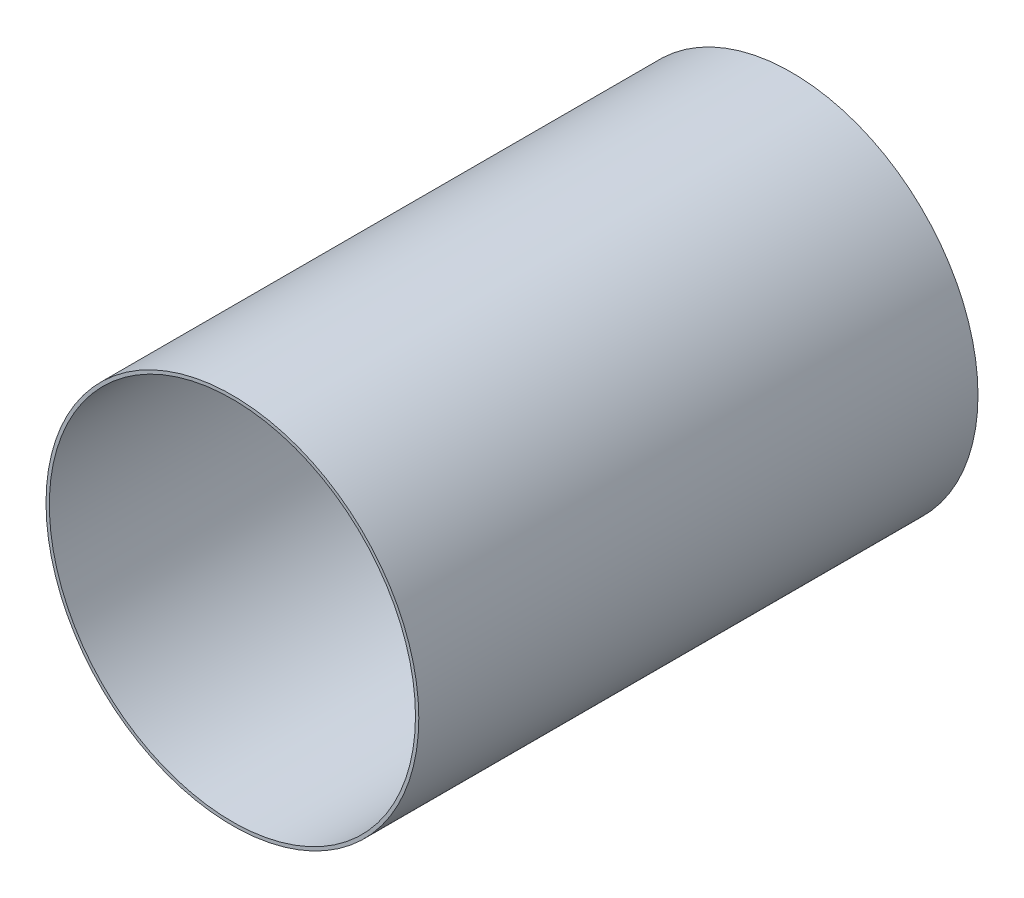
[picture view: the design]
ISO-10303-21;
HEADER;
FILE_DESCRIPTION(('STEP AP214'),'2;1');
FILE_NAME('part.step','',(''),(''),'','','');
FILE_SCHEMA(('AUTOMOTIVE_DESIGN { 1 0 10303 214 1 1 1 1 }'));
ENDSEC;
DATA;
#1=APPLICATION_CONTEXT('core data for automotive mechanical design processes');
#2=APPLICATION_PROTOCOL_DEFINITION('international standard','automotive_design',2000,#1);
#3=PRODUCT_CONTEXT('',#1,'mechanical');
#4=PRODUCT('Part','Part','',(#3));
#5=PRODUCT_RELATED_PRODUCT_CATEGORY('part','',(#4));
#6=PRODUCT_DEFINITION_FORMATION('','',#4);
#7=PRODUCT_DEFINITION_CONTEXT('part definition',#1,'design');
#8=PRODUCT_DEFINITION('design','',#6,#7);
#9=PRODUCT_DEFINITION_SHAPE('','',#8);
#10=(LENGTH_UNIT() NAMED_UNIT(*) SI_UNIT(.MILLI.,.METRE.));
#11=(NAMED_UNIT(*) PLANE_ANGLE_UNIT() SI_UNIT($,.RADIAN.));
#12=(NAMED_UNIT(*) SI_UNIT($,.STERADIAN.) SOLID_ANGLE_UNIT());
#13=UNCERTAINTY_MEASURE_WITH_UNIT(LENGTH_MEASURE(1.E-05),#10,'distance_accuracy_value','');
#14=(GEOMETRIC_REPRESENTATION_CONTEXT(3) GLOBAL_UNCERTAINTY_ASSIGNED_CONTEXT((#13)) GLOBAL_UNIT_ASSIGNED_CONTEXT((#10,
#11,#12)) REPRESENTATION_CONTEXT('',''));
#15=CARTESIAN_POINT('',(0.,0.,0.));
#16=DIRECTION('',(0.,0.,1.));
#17=DIRECTION('',(1.,0.,0.));
#18=AXIS2_PLACEMENT_3D('',#15,#16,#17);
#19=CARTESIAN_POINT('',(0.,0.,2133.6));
#20=DIRECTION('',(0.,0.,1.));
#21=DIRECTION('',(1.,0.,0.));
#22=AXIS2_PLACEMENT_3D('',#19,#20,#21);
#23=PLANE('',#22);
#24=CARTESIAN_POINT('',(0.,0.,2133.6));
#25=DIRECTION('',(0.,0.,1.));
#26=DIRECTION('',(1.,0.,0.));
#27=AXIS2_PLACEMENT_3D('',#24,#25,#26);
#28=CIRCLE('',#27,711.2);
#29=CARTESIAN_POINT('',(711.2,0.,2133.6));
#30=VERTEX_POINT('',#29);
#31=EDGE_CURVE('E10',#30,#30,#28,.T.);
#32=ORIENTED_EDGE('',*,*,#31,.T.);
#33=EDGE_LOOP('',(#32));
#34=FACE_BOUND('',#33,.T.);
#35=CARTESIAN_POINT('',(0.,0.,2133.6));
#36=DIRECTION('',(0.,0.,1.));
#37=DIRECTION('',(1.,0.,0.));
#38=AXIS2_PLACEMENT_3D('',#35,#36,#37);
#39=CIRCLE('',#38,698.5);
#40=CARTESIAN_POINT('',(698.5,0.,2133.6));
#41=VERTEX_POINT('',#40);
#42=EDGE_CURVE('E51',#41,#41,#39,.T.);
#43=ORIENTED_EDGE('',*,*,#42,.F.);
#44=EDGE_LOOP('',(#43));
#45=FACE_BOUND('',#44,.T.);
#46=ADVANCED_FACE('F32',(#34,#45),#23,.T.);
#47=CARTESIAN_POINT('',(0.,0.,0.));
#48=DIRECTION('',(0.,0.,1.));
#49=DIRECTION('',(1.,0.,0.));
#50=AXIS2_PLACEMENT_3D('',#47,#48,#49);
#51=PLANE('',#50);
#52=CARTESIAN_POINT('',(0.,0.,0.));
#53=DIRECTION('',(0.,0.,1.));
#54=DIRECTION('',(1.,0.,0.));
#55=AXIS2_PLACEMENT_3D('',#52,#53,#54);
#56=CIRCLE('',#55,711.2);
#57=CARTESIAN_POINT('',(711.2,0.,0.));
#58=VERTEX_POINT('',#57);
#59=EDGE_CURVE('E46',#58,#58,#56,.T.);
#60=ORIENTED_EDGE('',*,*,#59,.F.);
#61=EDGE_LOOP('',(#60));
#62=FACE_BOUND('',#61,.T.);
#63=CARTESIAN_POINT('',(0.,0.,0.));
#64=DIRECTION('',(0.,0.,1.));
#65=DIRECTION('',(1.,0.,0.));
#66=AXIS2_PLACEMENT_3D('',#63,#64,#65);
#67=CIRCLE('',#66,698.5);
#68=CARTESIAN_POINT('',(698.5,0.,0.));
#69=VERTEX_POINT('',#68);
#70=EDGE_CURVE('E53',#69,#69,#67,.T.);
#71=ORIENTED_EDGE('',*,*,#70,.T.);
#72=EDGE_LOOP('',(#71));
#73=FACE_BOUND('',#72,.T.);
#74=ADVANCED_FACE('F74',(#62,#73),#51,.F.);
#75=CARTESIAN_POINT('',(0.,0.,2133.6));
#76=DIRECTION('',(0.,0.,-1.));
#77=DIRECTION('',(-1.,0.,0.));
#78=AXIS2_PLACEMENT_3D('',#75,#76,#77);
#79=CYLINDRICAL_SURFACE('',#78,711.2);
#80=CARTESIAN_POINT('',(-711.2,0.,1071.5625));
#81=CARTESIAN_POINT('',(-711.199996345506,-4.13113994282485,1071.56249542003));
#82=CARTESIAN_POINT('',(-711.16398099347,-8.26258775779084,1071.47977653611));
#83=CARTESIAN_POINT('',(-711.020141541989,-16.5180823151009,1071.14909768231));
#84=CARTESIAN_POINT('',(-710.912306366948,-20.6421278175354,1070.90111222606));
#85=CARTESIAN_POINT('',(-710.625466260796,-28.8767675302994,1070.24039880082));
#86=CARTESIAN_POINT('',(-710.446423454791,-32.987353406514,1069.82758315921));
#87=CARTESIAN_POINT('',(-710.018370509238,-41.1849399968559,1068.83837206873));
#88=CARTESIAN_POINT('',(-709.769363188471,-45.2719416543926,1068.26198321));
#89=CARTESIAN_POINT('',(-709.202396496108,-53.424083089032,1066.94572322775));
#90=CARTESIAN_POINT('',(-708.884284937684,-57.4891539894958,1066.2054912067));
#91=CARTESIAN_POINT('',(-708.18152615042,-65.5809359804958,1064.56424978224));
#92=CARTESIAN_POINT('',(-707.796878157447,-69.6076466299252,1063.66323853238));
#93=CARTESIAN_POINT('',(-706.963617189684,-77.6149766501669,1061.70292681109));
#94=CARTESIAN_POINT('',(-706.515014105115,-81.5956030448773,1060.643650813));
#95=CARTESIAN_POINT('',(-705.556680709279,-89.5046269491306,1058.36935486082));
#96=CARTESIAN_POINT('',(-705.046950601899,-93.4330246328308,1057.15433542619));
#97=CARTESIAN_POINT('',(-703.971483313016,-101.217464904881,1054.57600474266));
#98=CARTESIAN_POINT('',(-703.405949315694,-105.073713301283,1053.21322980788));
#99=CARTESIAN_POINT('',(-702.220888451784,-112.721954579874,1050.33902208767));
#100=CARTESIAN_POINT('',(-701.601361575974,-116.513947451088,1048.82758927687));
#101=CARTESIAN_POINT('',(-700.312078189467,-124.02808090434,1045.65930647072));
#102=CARTESIAN_POINT('',(-699.642320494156,-127.750219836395,1044.0024530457));
#103=CARTESIAN_POINT('',(-698.256611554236,-135.119207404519,1040.54676856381));
#104=CARTESIAN_POINT('',(-697.540660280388,-138.766055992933,1038.74793741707));
#105=CARTESIAN_POINT('',(-696.067066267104,-145.978152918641,1035.01246595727));
#106=CARTESIAN_POINT('',(-695.309438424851,-149.543429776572,1033.07587481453));
#107=CARTESIAN_POINT('',(-693.7566859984,-156.588995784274,1029.06788260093));
#108=CARTESIAN_POINT('',(-692.961561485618,-160.069285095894,1026.99648178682));
#109=CARTESIAN_POINT('',(-691.338392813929,-166.940495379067,1022.72242513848));
#110=CARTESIAN_POINT('',(-690.510348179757,-170.331415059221,1020.51976740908));
#111=CARTESIAN_POINT('',(-688.826079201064,-177.019675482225,1015.98680379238));
#112=CARTESIAN_POINT('',(-687.969854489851,-180.317015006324,1013.65649624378));
#113=CARTESIAN_POINT('',(-686.19141053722,-186.973884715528,1008.75417774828));
#114=CARTESIAN_POINT('',(-685.268016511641,-190.328499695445,1006.17591614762));
#115=CARTESIAN_POINT('',(-683.401318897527,-196.925951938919,1000.88697345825));
#116=CARTESIAN_POINT('',(-682.458015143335,-200.168788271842,998.17629126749));
#117=CARTESIAN_POINT('',(-680.557390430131,-206.538433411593,992.626666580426));
#118=CARTESIAN_POINT('',(-679.600069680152,-209.665243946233,989.787725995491));
#119=CARTESIAN_POINT('',(-677.677307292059,-215.799069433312,983.985420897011));
#120=CARTESIAN_POINT('',(-676.711865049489,-218.8060753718,981.022047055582));
#121=CARTESIAN_POINT('',(-674.778525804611,-224.697569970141,974.97364991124));
#122=CARTESIAN_POINT('',(-673.810627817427,-227.58199671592,971.888566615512));
#123=CARTESIAN_POINT('',(-671.879027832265,-233.222854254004,965.602249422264));
#124=CARTESIAN_POINT('',(-670.915325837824,-235.979284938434,962.401015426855));
#125=CARTESIAN_POINT('',(-668.998290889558,-241.360488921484,955.886323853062));
#126=CARTESIAN_POINT('',(-668.044958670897,-243.985252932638,952.572858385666));
#127=CARTESIAN_POINT('',(-666.155107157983,-249.098861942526,945.838441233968));
#128=CARTESIAN_POINT('',(-665.218586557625,-251.587717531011,942.417497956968));
#129=CARTESIAN_POINT('',(-663.317723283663,-256.558967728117,935.281195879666));
#130=CARTESIAN_POINT('',(-662.354683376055,-259.033478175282,931.559992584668));
#131=CARTESIAN_POINT('',(-660.461716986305,-263.822650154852,924.007850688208));
#132=CARTESIAN_POINT('',(-659.531790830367,-266.137310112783,920.176911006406));
#133=CARTESIAN_POINT('',(-657.712428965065,-270.602315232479,912.410743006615));
#134=CARTESIAN_POINT('',(-656.8229954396,-272.75265153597,908.475509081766));
#135=CARTESIAN_POINT('',(-655.092019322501,-276.884277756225,900.506966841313));
#136=CARTESIAN_POINT('',(-654.250476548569,-278.865568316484,896.473658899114));
#137=CARTESIAN_POINT('',(-652.622823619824,-282.653743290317,888.317116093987));
#138=CARTESIAN_POINT('',(-651.836690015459,-284.4607016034,884.19392025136));
#139=CARTESIAN_POINT('',(-650.32642798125,-287.896681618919,875.862834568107));
#140=CARTESIAN_POINT('',(-649.602299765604,-289.525702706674,871.654944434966));
#141=CARTESIAN_POINT('',(-648.222752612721,-292.601339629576,863.162209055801));
#142=CARTESIAN_POINT('',(-647.567329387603,-294.047966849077,858.877368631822));
#143=CARTESIAN_POINT('',(-646.331389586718,-296.75476252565,850.238542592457));
#144=CARTESIAN_POINT('',(-645.750872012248,-298.014933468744,845.88455789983));
#145=CARTESIAN_POINT('',(-644.698085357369,-300.285369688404,837.34033540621));
#146=CARTESIAN_POINT('',(-644.221798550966,-301.305119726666,833.153111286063));
#147=CARTESIAN_POINT('',(-643.346153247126,-303.170297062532,824.732048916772));
#148=CARTESIAN_POINT('',(-642.94679393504,-304.01572620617,820.498211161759));
#149=CARTESIAN_POINT('',(-642.228752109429,-305.529658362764,811.992294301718));
#150=CARTESIAN_POINT('',(-641.910068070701,-306.19816472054,807.720215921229));
#151=CARTESIAN_POINT('',(-641.356419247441,-307.356138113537,799.146442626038));
#152=CARTESIAN_POINT('',(-641.12145454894,-307.845604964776,794.844747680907));
#153=CARTESIAN_POINT('',(-640.737638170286,-308.643670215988,786.223099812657));
#154=CARTESIAN_POINT('',(-640.588740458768,-308.952365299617,781.903157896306));
#155=CARTESIAN_POINT('',(-640.378330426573,-309.388255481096,773.251975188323));
#156=CARTESIAN_POINT('',(-640.316818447,-309.51544987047,768.920734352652));
#157=CARTESIAN_POINT('',(-640.281791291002,-309.587902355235,760.256609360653));
#158=CARTESIAN_POINT('',(-640.30827150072,-309.533169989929,755.923725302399));
#159=CARTESIAN_POINT('',(-640.448957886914,-309.241974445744,747.265550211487));
#160=CARTESIAN_POINT('',(-640.563162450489,-309.005514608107,742.940259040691));
#161=CARTESIAN_POINT('',(-640.864723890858,-308.379562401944,734.674739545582));
#162=CARTESIAN_POINT('',(-641.045013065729,-308.004837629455,730.73312456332));
#163=CARTESIAN_POINT('',(-641.476552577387,-307.105066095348,722.871051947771));
#164=CARTESIAN_POINT('',(-641.727801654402,-306.580022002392,718.950593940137));
#165=CARTESIAN_POINT('',(-642.299212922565,-305.38107630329,711.137853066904));
#166=CARTESIAN_POINT('',(-642.619370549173,-304.707184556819,707.245568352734));
#167=CARTESIAN_POINT('',(-643.326067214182,-303.212292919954,699.49542547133));
#168=CARTESIAN_POINT('',(-643.712606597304,-302.391292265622,695.637567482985));
#169=CARTESIAN_POINT('',(-644.549121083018,-300.604131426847,687.961988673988));
#170=CARTESIAN_POINT('',(-644.999105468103,-299.637949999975,684.144273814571));
#171=CARTESIAN_POINT('',(-645.959050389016,-297.562853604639,676.555494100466));
#172=CARTESIAN_POINT('',(-646.469010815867,-296.453938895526,672.784429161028));
#173=CARTESIAN_POINT('',(-647.545157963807,-294.095882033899,665.294419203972));
#174=CARTESIAN_POINT('',(-648.111346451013,-292.846735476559,661.575475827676));
#175=CARTESIAN_POINT('',(-649.295874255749,-290.210949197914,654.195078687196));
#176=CARTESIAN_POINT('',(-649.914213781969,-288.824308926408,650.533625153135));
#177=CARTESIAN_POINT('',(-651.212893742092,-285.884322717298,643.193142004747));
#178=CARTESIAN_POINT('',(-651.894300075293,-284.327976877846,639.515502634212));
#179=CARTESIAN_POINT('',(-653.302294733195,-281.077726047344,632.230346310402));
#180=CARTESIAN_POINT('',(-654.028883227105,-279.383820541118,628.622829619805));
#181=CARTESIAN_POINT('',(-655.522250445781,-275.861700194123,621.482706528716));
#182=CARTESIAN_POINT('',(-656.289027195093,-274.03349195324,617.950096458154));
#183=CARTESIAN_POINT('',(-657.857806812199,-270.245718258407,610.96363317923));
#184=CARTESIAN_POINT('',(-658.659812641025,-268.286141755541,607.50978662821));
#185=CARTESIAN_POINT('',(-660.294055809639,-264.238461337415,600.684398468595));
#186=CARTESIAN_POINT('',(-661.126300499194,-262.15032608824,597.312877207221));
#187=CARTESIAN_POINT('',(-662.815719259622,-257.848989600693,590.656651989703));
#188=CARTESIAN_POINT('',(-663.672895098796,-255.635779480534,587.371954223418));
#189=CARTESIAN_POINT('',(-665.406937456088,-251.087575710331,580.893303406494));
#190=CARTESIAN_POINT('',(-666.283804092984,-248.752581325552,577.699350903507));
#191=CARTESIAN_POINT('',(-668.052051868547,-243.963953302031,571.405754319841));
#192=CARTESIAN_POINT('',(-668.943433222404,-241.510317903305,568.306111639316));
#193=CARTESIAN_POINT('',(-670.819043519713,-236.253564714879,561.92038299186));
#194=CARTESIAN_POINT('',(-671.804186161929,-233.439183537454,558.643828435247));
#195=CARTESIAN_POINT('',(-673.778904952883,-227.67675080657,552.212297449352));
#196=CARTESIAN_POINT('',(-674.768480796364,-224.728708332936,549.057312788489));
#197=CARTESIAN_POINT('',(-676.74568166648,-218.70249113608,542.872626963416));
#198=CARTESIAN_POINT('',(-677.733306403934,-215.624298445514,539.842943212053));
#199=CARTESIAN_POINT('',(-679.699867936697,-209.342685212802,533.913979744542));
#200=CARTESIAN_POINT('',(-680.678805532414,-206.13927635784,531.01468791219));
#201=CARTESIAN_POINT('',(-682.622009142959,-199.610213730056,525.349645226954));
#202=CARTESIAN_POINT('',(-683.586270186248,-196.284519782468,522.583938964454));
#203=CARTESIAN_POINT('',(-685.493500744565,-189.516388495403,517.19150073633));
#204=CARTESIAN_POINT('',(-686.436470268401,-186.073951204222,514.564768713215));
#205=CARTESIAN_POINT('',(-688.294968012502,-179.077021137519,509.454698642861));
#206=CARTESIAN_POINT('',(-689.210496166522,-175.52252809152,506.971360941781));
#207=CARTESIAN_POINT('',(-691.008110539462,-168.306437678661,502.152529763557));
#208=CARTESIAN_POINT('',(-691.890196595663,-164.644839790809,499.81703700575));
#209=CARTESIAN_POINT('',(-693.638735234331,-157.118038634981,495.236434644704));
#210=CARTESIAN_POINT('',(-694.50409708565,-153.250005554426,492.995555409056));
#211=CARTESIAN_POINT('',(-696.187268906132,-145.412487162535,488.679375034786));
#212=CARTESIAN_POINT('',(-697.005078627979,-141.443001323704,486.604074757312));
#213=CARTESIAN_POINT('',(-698.58733315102,-133.408922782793,482.623732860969));
#214=CARTESIAN_POINT('',(-699.351775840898,-129.344326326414,480.718697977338));
#215=CARTESIAN_POINT('',(-700.821713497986,-121.127148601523,477.083628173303));
#216=CARTESIAN_POINT('',(-701.527208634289,-116.974567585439,475.353592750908));
#217=CARTESIAN_POINT('',(-702.873730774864,-108.590858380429,472.073771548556));
#218=CARTESIAN_POINT('',(-703.514788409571,-104.359768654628,470.523900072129));
#219=CARTESIAN_POINT('',(-704.728019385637,-95.8250317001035,467.607674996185));
#220=CARTESIAN_POINT('',(-705.300192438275,-91.5213841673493,466.24132216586));
#221=CARTESIAN_POINT('',(-706.371256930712,-82.8502850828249,463.696150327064));
#222=CARTESIAN_POINT('',(-706.870153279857,-78.4828378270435,462.517318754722));
#223=CARTESIAN_POINT('',(-707.79084372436,-69.6928131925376,460.350630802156));
#224=CARTESIAN_POINT('',(-708.21263910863,-65.2702367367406,459.362771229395));
#225=CARTESIAN_POINT('',(-708.949960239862,-56.6806478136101,457.641477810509));
#226=CARTESIAN_POINT('',(-709.270750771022,-52.5166283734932,456.895338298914));
#227=CARTESIAN_POINT('',(-709.840247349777,-44.1567134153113,455.57377072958));
#228=CARTESIAN_POINT('',(-710.088954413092,-39.9608183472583,454.998340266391));
#229=CARTESIAN_POINT('',(-710.512544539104,-31.5454133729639,454.01985150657));
#230=CARTESIAN_POINT('',(-710.687430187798,-27.3259042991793,453.616787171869));
#231=CARTESIAN_POINT('',(-710.962162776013,-18.8714422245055,452.984175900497));
#232=CARTESIAN_POINT('',(-711.062009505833,-14.6364891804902,452.754629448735));
#233=CARTESIAN_POINT('',(-711.185941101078,-6.16079425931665,452.469774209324));
#234=CARTESIAN_POINT('',(-711.210046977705,-1.92005431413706,452.414417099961));
#235=CARTESIAN_POINT('',(-711.182385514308,6.55988076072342,452.477968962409));
#236=CARTESIAN_POINT('',(-711.130618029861,10.7990758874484,452.596878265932));
#237=CARTESIAN_POINT('',(-710.951578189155,19.2673039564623,453.008604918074));
#238=CARTESIAN_POINT('',(-710.824307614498,23.4963371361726,453.301418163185));
#239=CARTESIAN_POINT('',(-710.495159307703,31.9359003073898,454.060087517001));
#240=CARTESIAN_POINT('',(-710.293282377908,36.1464304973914,454.525941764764));
#241=CARTESIAN_POINT('',(-709.829537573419,44.3084649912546,455.598802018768));
#242=CARTESIAN_POINT('',(-709.571606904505,48.2614113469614,456.196572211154));
#243=CARTESIAN_POINT('',(-708.992036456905,56.1366237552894,457.543797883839));
#244=CARTESIAN_POINT('',(-708.670397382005,60.0588901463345,458.293251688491));
#245=CARTESIAN_POINT('',(-707.965400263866,67.8659973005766,459.941951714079));
#246=CARTESIAN_POINT('',(-707.582045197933,71.7508398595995,460.841190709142));
#247=CARTESIAN_POINT('',(-706.755929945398,79.4769752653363,462.787329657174));
#248=CARTESIAN_POINT('',(-706.31316955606,83.3182679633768,463.834230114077));
#249=CARTESIAN_POINT('',(-705.370867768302,90.9514619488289,466.073330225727));
#250=CARTESIAN_POINT('',(-704.871322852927,94.74336016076,467.265538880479));
#251=CARTESIAN_POINT('',(-703.818426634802,102.271739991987,469.792542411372));
#252=CARTESIAN_POINT('',(-703.265075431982,106.008221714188,471.127337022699));
#253=CARTESIAN_POINT('',(-702.107770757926,113.420407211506,473.936705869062));
#254=CARTESIAN_POINT('',(-701.503815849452,117.096109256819,475.411284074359));
#255=CARTESIAN_POINT('',(-700.248780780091,124.381462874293,478.497190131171));
#256=CARTESIAN_POINT('',(-699.597700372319,127.9911141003,480.108518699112));
#257=CARTESIAN_POINT('',(-698.23109518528,135.251039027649,483.517187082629));
#258=CARTESIAN_POINT('',(-697.514193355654,138.899065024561,485.318762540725));
#259=CARTESIAN_POINT('',(-696.038438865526,146.114656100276,489.060509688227));
#260=CARTESIAN_POINT('',(-695.279585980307,149.68222074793,491.000682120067));
#261=CARTESIAN_POINT('',(-693.724369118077,156.732159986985,495.016053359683));
#262=CARTESIAN_POINT('',(-692.928005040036,160.2145343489,497.091252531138));
#263=CARTESIAN_POINT('',(-691.302374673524,167.08962981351,501.373068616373));
#264=CARTESIAN_POINT('',(-690.473108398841,170.482350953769,503.579685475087));
#265=CARTESIAN_POINT('',(-688.786130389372,177.175112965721,508.121521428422));
#266=CARTESIAN_POINT('',(-687.92840881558,180.475121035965,510.456785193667));
#267=CARTESIAN_POINT('',(-686.189683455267,186.977227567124,515.251596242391));
#268=CARTESIAN_POINT('',(-685.308679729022,190.179326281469,517.711143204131));
#269=CARTESIAN_POINT('',(-683.528387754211,196.481820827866,522.750933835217));
#270=CARTESIAN_POINT('',(-682.629099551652,199.582216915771,525.331177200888));
#271=CARTESIAN_POINT('',(-680.817259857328,205.677927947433,530.609018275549));
#272=CARTESIAN_POINT('',(-679.904707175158,208.67323337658,533.306626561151));
#273=CARTESIAN_POINT('',(-678.000449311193,214.783261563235,539.029272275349));
#274=CARTESIAN_POINT('',(-677.008098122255,217.889208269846,542.063472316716));
#275=CARTESIAN_POINT('',(-675.020706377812,223.970352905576,548.259350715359));
#276=CARTESIAN_POINT('',(-674.025665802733,226.945549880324,551.421030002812));
#277=CARTESIAN_POINT('',(-672.039540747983,232.761117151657,557.86756924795));
#278=CARTESIAN_POINT('',(-671.048456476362,235.601480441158,561.152435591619));
#279=CARTESIAN_POINT('',(-669.077078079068,241.143012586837,567.840660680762));
#280=CARTESIAN_POINT('',(-668.096783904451,243.844182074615,571.244018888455));
#281=CARTESIAN_POINT('',(-666.153510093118,249.104002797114,578.165734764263));
#282=CARTESIAN_POINT('',(-665.190536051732,251.662608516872,581.684128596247));
#283=CARTESIAN_POINT('',(-663.289082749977,256.6322492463,588.830223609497));
#284=CARTESIAN_POINT('',(-662.35060411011,259.043280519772,592.457927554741));
#285=CARTESIAN_POINT('',(-660.50502627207,263.713585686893,599.817752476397));
#286=CARTESIAN_POINT('',(-659.59792833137,265.972853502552,603.549877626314));
#287=CARTESIAN_POINT('',(-657.82211300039,270.335075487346,611.112813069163));
#288=CARTESIAN_POINT('',(-656.953391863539,272.438044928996,614.943613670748));
#289=CARTESIAN_POINT('',(-655.243777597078,276.524932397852,622.777810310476));
#290=CARTESIAN_POINT('',(-654.403813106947,278.505548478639,626.783132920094));
#291=CARTESIAN_POINT('',(-652.777917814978,282.295380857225,634.884857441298));
#292=CARTESIAN_POINT('',(-651.991987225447,284.104596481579,638.981259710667));
#293=CARTESIAN_POINT('',(-650.481013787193,287.547257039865,647.258516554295));
#294=CARTESIAN_POINT('',(-649.755973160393,289.180695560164,651.439374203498));
#295=CARTESIAN_POINT('',(-648.373395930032,292.267411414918,659.878081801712));
#296=CARTESIAN_POINT('',(-647.715859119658,293.720689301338,664.135931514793));
#297=CARTESIAN_POINT('',(-646.474943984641,296.441936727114,672.717493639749));
#298=CARTESIAN_POINT('',(-645.891509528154,297.71004663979,677.041153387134));
#299=CARTESIAN_POINT('',(-644.803876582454,300.058453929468,685.74909085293));
#300=CARTESIAN_POINT('',(-644.299678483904,301.138750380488,690.133368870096));
#301=CARTESIAN_POINT('',(-643.375610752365,303.107978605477,698.953117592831));
#302=CARTESIAN_POINT('',(-642.955733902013,303.996926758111,703.388583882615));
#303=CARTESIAN_POINT('',(-642.204582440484,305.580567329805,712.301470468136));
#304=CARTESIAN_POINT('',(-641.873305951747,306.275263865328,716.77888987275));
#305=CARTESIAN_POINT('',(-641.326318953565,307.418866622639,725.395570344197));
#306=CARTESIAN_POINT('',(-641.103338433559,307.88330195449,729.532316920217));
#307=CARTESIAN_POINT('',(-640.736912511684,308.64514917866,737.824637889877));
#308=CARTESIAN_POINT('',(-640.59346570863,308.942564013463,741.980211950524));
#309=CARTESIAN_POINT('',(-640.387418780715,309.369439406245,750.30177972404));
#310=CARTESIAN_POINT('',(-640.324814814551,309.498907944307,754.467772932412));
#311=CARTESIAN_POINT('',(-640.281014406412,309.589510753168,762.802036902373));
#312=CARTESIAN_POINT('',(-640.29981827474,309.550644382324,766.970307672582));
#313=CARTESIAN_POINT('',(-640.418651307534,309.304719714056,775.299994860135));
#314=CARTESIAN_POINT('',(-640.51866636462,309.097690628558,779.461412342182));
#315=CARTESIAN_POINT('',(-640.798988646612,308.516126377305,787.769810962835));
#316=CARTESIAN_POINT('',(-640.979296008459,308.141590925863,791.916792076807));
#317=CARTESIAN_POINT('',(-641.418562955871,307.226178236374,800.188085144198));
#318=CARTESIAN_POINT('',(-641.677521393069,306.685303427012,804.312397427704));
#319=CARTESIAN_POINT('',(-642.271773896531,305.438840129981,812.530472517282));
#320=CARTESIAN_POINT('',(-642.607067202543,304.733253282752,816.624235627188));
#321=CARTESIAN_POINT('',(-643.330373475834,303.203142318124,824.547252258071));
#322=CARTESIAN_POINT('',(-643.714424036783,302.38740066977,828.378568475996));
#323=CARTESIAN_POINT('',(-644.545032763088,300.61287459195,836.001037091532));
#324=CARTESIAN_POINT('',(-644.991590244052,299.654091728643,839.792189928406));
#325=CARTESIAN_POINT('',(-645.943847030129,297.595819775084,847.328344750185));
#326=CARTESIAN_POINT('',(-646.449543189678,296.496338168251,851.073349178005));
#327=CARTESIAN_POINT('',(-647.51641365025,294.159113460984,858.511949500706));
#328=CARTESIAN_POINT('',(-648.077588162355,292.921369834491,862.205545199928));
#329=CARTESIAN_POINT('',(-649.251557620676,290.310014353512,869.536886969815));
#330=CARTESIAN_POINT('',(-649.864362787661,288.936375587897,873.174621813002));
#331=CARTESIAN_POINT('',(-651.137285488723,286.056208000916,880.38864711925));
#332=CARTESIAN_POINT('',(-651.797402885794,284.549679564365,883.964937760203));
#333=CARTESIAN_POINT('',(-653.160584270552,281.406512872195,891.051702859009));
#334=CARTESIAN_POINT('',(-653.863649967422,279.769869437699,894.562174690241));
#335=CARTESIAN_POINT('',(-655.308175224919,276.369404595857,901.512950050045));
#336=CARTESIAN_POINT('',(-656.049635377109,274.605581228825,904.953252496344));
#337=CARTESIAN_POINT('',(-657.614010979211,270.838824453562,911.973743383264));
#338=CARTESIAN_POINT('',(-658.439116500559,268.827829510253,915.549120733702));
#339=CARTESIAN_POINT('',(-660.121811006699,264.668975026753,922.611547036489));
#340=CARTESIAN_POINT('',(-660.97940032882,262.521114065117,926.098595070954));
#341=CARTESIAN_POINT('',(-662.721345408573,258.092077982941,932.980007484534));
#342=CARTESIAN_POINT('',(-663.605700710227,255.81090513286,936.374373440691));
#343=CARTESIAN_POINT('',(-665.395544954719,251.118526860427,943.066643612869));
#344=CARTESIAN_POINT('',(-666.301035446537,248.707311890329,946.364540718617));
#345=CARTESIAN_POINT('',(-668.12765135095,243.757752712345,952.86062604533));
#346=CARTESIAN_POINT('',(-669.048781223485,241.219371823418,956.058785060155));
#347=CARTESIAN_POINT('',(-670.900743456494,236.019594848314,962.350563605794));
#348=CARTESIAN_POINT('',(-671.83157580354,233.358198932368,965.444183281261));
#349=CARTESIAN_POINT('',(-673.697387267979,227.915656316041,971.523365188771));
#350=CARTESIAN_POINT('',(-674.632366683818,225.134500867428,974.5089194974));
#351=CARTESIAN_POINT('',(-676.500768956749,219.456333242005,980.367809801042));
#352=CARTESIAN_POINT('',(-677.434191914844,216.559328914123,983.241153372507));
#353=CARTESIAN_POINT('',(-679.370905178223,210.408765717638,989.104835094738));
#354=CARTESIAN_POINT('',(-680.373596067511,207.145523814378,992.085224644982));
#355=CARTESIAN_POINT('',(-682.363937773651,200.491782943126,997.905753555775));
#356=CARTESIAN_POINT('',(-683.351588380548,197.101282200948,1000.74589095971));
#357=CARTESIAN_POINT('',(-685.305174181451,190.197602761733,1006.28137465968));
#358=CARTESIAN_POINT('',(-686.271107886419,186.684415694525,1008.97671104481));
#359=CARTESIAN_POINT('',(-688.174593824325,179.540614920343,1014.21763244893));
#360=CARTESIAN_POINT('',(-689.112146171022,175.910001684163,1016.76321806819));
#361=CARTESIAN_POINT('',(-690.952941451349,168.534643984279,1021.70121384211));
#362=CARTESIAN_POINT('',(-691.85616575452,164.789839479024,1024.09354129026));
#363=CARTESIAN_POINT('',(-693.62153112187,157.193562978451,1028.71876394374));
#364=CARTESIAN_POINT('',(-694.483672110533,153.34209078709,1030.95165885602));
#365=CARTESIAN_POINT('',(-696.160786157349,145.538739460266,1035.25311328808));
#366=CARTESIAN_POINT('',(-696.975762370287,141.586867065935,1037.32168380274));
#367=CARTESIAN_POINT('',(-698.552834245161,133.588887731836,1041.28995473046));
#368=CARTESIAN_POINT('',(-699.314930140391,129.542781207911,1043.18965588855));
#369=CARTESIAN_POINT('',(-700.771040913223,121.417448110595,1046.79155620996));
#370=CARTESIAN_POINT('',(-701.465824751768,117.339372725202,1048.49604085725));
#371=CARTESIAN_POINT('',(-702.793631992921,109.105185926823,1051.73188929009));
#372=CARTESIAN_POINT('',(-703.426655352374,104.949074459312,1053.26325295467));
#373=CARTESIAN_POINT('',(-704.626467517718,96.5655979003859,1056.14908245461));
#374=CARTESIAN_POINT('',(-705.193244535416,92.3382202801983,1057.50351681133));
#375=CARTESIAN_POINT('',(-706.25625815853,83.8209729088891,1060.03140573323));
#376=CARTESIAN_POINT('',(-706.752495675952,79.5311039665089,1061.20486263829));
#377=CARTESIAN_POINT('',(-707.66946036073,70.9092178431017,1063.36443007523));
#378=CARTESIAN_POINT('',(-708.090392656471,66.5773501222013,1064.35104998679));
#379=CARTESIAN_POINT('',(-708.855273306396,57.8683798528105,1066.13804794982));
#380=CARTESIAN_POINT('',(-709.199218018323,53.4912751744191,1066.9384171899));
#381=CARTESIAN_POINT('',(-709.807278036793,44.7040615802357,1068.34992841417));
#382=CARTESIAN_POINT('',(-710.071443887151,40.2939753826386,1068.96119021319));
#383=CARTESIAN_POINT('',(-710.518167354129,31.4480376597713,1069.99315702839));
#384=CARTESIAN_POINT('',(-710.700739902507,27.0121909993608,1070.4138969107));
#385=CARTESIAN_POINT('',(-710.901422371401,20.6914727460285,1070.87594225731));
#386=CARTESIAN_POINT('',(-710.953614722,18.8131088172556,1070.99603874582));
#387=CARTESIAN_POINT('',(-711.043131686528,15.0544745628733,1071.20194929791));
#388=CARTESIAN_POINT('',(-711.080459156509,13.1742046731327,1071.28776994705));
#389=CARTESIAN_POINT('',(-711.140204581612,9.41215484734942,1071.42510529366));
#390=CARTESIAN_POINT('',(-711.162622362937,7.53037489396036,1071.47661959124));
#391=CARTESIAN_POINT('',(-711.192522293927,3.76575136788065,1071.54532118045));
#392=CARTESIAN_POINT('',(-711.20000166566,1.88290766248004,1071.56250208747));
#393=CARTESIAN_POINT('',(-711.2,0.,1071.5625));
#394=B_SPLINE_CURVE_WITH_KNOTS('',3,(#80,#81,#82,#83,#84,#85,#86,#87,#88,#89,#90,#91,#92,#93,
#94,#95,#96,#97,#98,#99,#100,#101,#102,#103,#104,#105,#106,#107,#108,#109,#110,#111,#112,#113,
#114,#115,#116,#117,#118,#119,#120,#121,#122,#123,#124,#125,#126,#127,#128,#129,#130,#131,#132,
#133,#134,#135,#136,#137,#138,#139,#140,#141,#142,#143,#144,#145,#146,#147,#148,#149,#150,#151,
#152,#153,#154,#155,#156,#157,#158,#159,#160,#161,#162,#163,#164,#165,#166,#167,#168,#169,#170,
#171,#172,#173,#174,#175,#176,#177,#178,#179,#180,#181,#182,#183,#184,#185,#186,#187,#188,#189,
#190,#191,#192,#193,#194,#195,#196,#197,#198,#199,#200,#201,#202,#203,#204,#205,#206,#207,#208,
#209,#210,#211,#212,#213,#214,#215,#216,#217,#218,#219,#220,#221,#222,#223,#224,#225,#226,#227,
#228,#229,#230,#231,#232,#233,#234,#235,#236,#237,#238,#239,#240,#241,#242,#243,#244,#245,#246,
#247,#248,#249,#250,#251,#252,#253,#254,#255,#256,#257,#258,#259,#260,#261,#262,#263,#264,#265,
#266,#267,#268,#269,#270,#271,#272,#273,#274,#275,#276,#277,#278,#279,#280,#281,#282,#283,#284,
#285,#286,#287,#288,#289,#290,#291,#292,#293,#294,#295,#296,#297,#298,#299,#300,#301,#302,#303,
#304,#305,#306,#307,#308,#309,#310,#311,#312,#313,#314,#315,#316,#317,#318,#319,#320,#321,#322,
#323,#324,#325,#326,#327,#328,#329,#330,#331,#332,#333,#334,#335,#336,#337,#338,#339,#340,#341,
#342,#343,#344,#345,#346,#347,#348,#349,#350,#351,#352,#353,#354,#355,#356,#357,#358,#359,#360,
#361,#362,#363,#364,#365,#366,#367,#368,#369,#370,#371,#372,#373,#374,#375,#376,#377,#378,#379,
#380,#381,#382,#383,#384,#385,#386,#387,#388,#389,#390,#391,#392,#393),.UNSPECIFIED.,.T.,.F.,(4,
2,2,2,2,2,2,2,2,2,2,2,2,2,2,2,2,2,2,2,2,2,2,2,2,2,2,2,2,2,2,2,2,2,2,2,2,2,2,2,2,2,2,2,2,2,2,2,2,
2,2,2,2,2,2,2,2,2,2,2,2,2,2,2,2,2,2,2,2,2,2,2,2,2,2,2,2,2,2,2,2,2,2,2,2,2,2,2,2,2,2,2,2,2,2,2,2,
2,2,2,2,2,2,2,2,2,2,2,2,2,2,2,2,2,2,2,2,2,2,2,2,2,2,2,2,2,2,2,2,2,2,2,2,2,2,2,2,2,2,2,2,2,2,2,2,
2,2,2,2,2,2,2,2,2,2,2,4),(0.,12.3929694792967,24.7878505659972,37.1893332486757,
49.5903163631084,62.0188918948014,74.4476101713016,86.8744085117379,99.3011654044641,
111.684237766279,124.067312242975,136.45067884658,148.834053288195,161.213029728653,
173.591982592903,185.971114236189,198.350407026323,211.33844532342,224.326591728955,
237.314544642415,250.30347291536,263.298885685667,276.294309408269,289.290648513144,
302.285973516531,315.996042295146,329.706246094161,343.417188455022,357.128078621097,
370.833130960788,384.538230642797,398.242474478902,411.946535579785,424.949735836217,
437.952798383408,450.95561508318,463.958445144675,476.954314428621,489.950234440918,
502.945473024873,515.940472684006,527.827441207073,539.714198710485,551.600169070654,
563.486201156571,575.373974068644,587.26172538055,599.149850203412,611.038022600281,
623.188129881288,635.338282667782,647.487838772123,659.638418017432,671.791970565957,
683.946387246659,696.100877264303,708.255547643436,721.542526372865,734.828603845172,
748.116521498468,761.403201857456,774.694287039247,787.985366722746,801.276478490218,
814.567654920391,828.2230384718,841.878493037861,855.534487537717,869.190442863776,
882.839875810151,896.489365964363,910.13794122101,923.78628829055,936.509658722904,
949.232849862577,961.955595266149,974.678376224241,987.397627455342,1000.11690289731,
1012.83587822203,1025.55471676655,1037.56984067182,1049.58483185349,1061.59924358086,
1073.61369631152,1085.62889356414,1097.64406850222,1109.65958480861,1121.67516406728,
1134.06571703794,1146.45633638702,1158.84698911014,1171.23763664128,1183.63261408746,
1196.02755944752,1208.42247362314,1220.81850711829,1234.17668180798,1247.53495398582,
1260.89391961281,1274.2528246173,1287.61597043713,1300.97945443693,1314.3434733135,
1327.7061846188,1341.34137296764,1354.97661488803,1368.61235415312,1382.24805164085,
1395.87335781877,1409.49873117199,1423.12293778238,1436.74685565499,1449.24890840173,
1461.75074088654,1474.2519793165,1486.75326539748,1499.25238031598,1511.75151655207,
1524.25047029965,1536.74929957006,1548.55393276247,1560.35843671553,1572.16231307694,
1583.96623435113,1595.77249783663,1607.57872713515,1619.38542658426,1631.19230799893,
1643.74178872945,1656.29139981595,1668.84079723,1681.39111728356,1693.94507856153,
1706.49902246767,1719.05388497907,1731.60789831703,1745.19916158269,1758.79061440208,
1772.38299630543,1785.97532372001,1799.57492555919,1813.17455239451,1826.77326851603,
1840.37192463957,1853.790204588,1867.20849391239,1880.62916732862,1894.04966721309,
1907.43303431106,1920.81703443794,1934.19253727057,1947.56559135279,1953.21407894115,
1958.8614807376,1964.50894836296,1970.15746608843),.UNSPECIFIED.);
#395=CARTESIAN_POINT('',(-711.2,0.,1071.5625));
#396=VERTEX_POINT('',#395);
#397=EDGE_CURVE('E56',#396,#396,#394,.T.);
#398=ORIENTED_EDGE('',*,*,#397,.T.);
#399=EDGE_LOOP('',(#398));
#400=FACE_BOUND('',#399,.T.);
#401=ORIENTED_EDGE('',*,*,#31,.F.);
#402=EDGE_LOOP('',(#401));
#403=FACE_BOUND('',#402,.T.);
#404=ORIENTED_EDGE('',*,*,#59,.T.);
#405=EDGE_LOOP('',(#404));
#406=FACE_BOUND('',#405,.T.);
#407=ADVANCED_FACE('F34',(#400,#403,#406),#79,.T.);
#408=CARTESIAN_POINT('',(0.,0.,2133.6));
#409=DIRECTION('',(0.,0.,-1.));
#410=DIRECTION('',(-1.,0.,0.));
#411=AXIS2_PLACEMENT_3D('',#408,#409,#410);
#412=CYLINDRICAL_SURFACE('',#411,698.5);
#413=CARTESIAN_POINT('',(-698.5,0.,1071.5625));
#414=CARTESIAN_POINT('',(-698.499996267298,-4.1240190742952,1071.56249536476));
#415=CARTESIAN_POINT('',(-698.46345271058,-8.24832034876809,1071.48006179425));
#416=CARTESIAN_POINT('',(-698.317503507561,-16.4895119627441,1071.15052690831));
#417=CARTESIAN_POINT('',(-698.208086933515,-20.6064010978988,1070.90340089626));
#418=CARTESIAN_POINT('',(-697.917041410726,-28.8266446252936,1070.24499261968));
#419=CARTESIAN_POINT('',(-697.735375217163,-32.9299909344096,1069.83362568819));
#420=CARTESIAN_POINT('',(-697.301047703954,-41.1130960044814,1068.8479072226));
#421=CARTESIAN_POINT('',(-697.04838916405,-45.1928556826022,1068.27356206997));
#422=CARTESIAN_POINT('',(-696.473119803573,-53.330258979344,1066.9620402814));
#423=CARTESIAN_POINT('',(-696.150358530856,-57.3878354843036,1066.22451336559));
#424=CARTESIAN_POINT('',(-695.437321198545,-65.4646354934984,1064.58932629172));
#425=CARTESIAN_POINT('',(-695.047044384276,-69.4838585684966,1063.69166434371));
#426=CARTESIAN_POINT('',(-694.201574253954,-77.4762571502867,1061.73870570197));
#427=CARTESIAN_POINT('',(-693.746390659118,-81.4494394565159,1060.68343261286));
#428=CARTESIAN_POINT('',(-692.773977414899,-89.3436192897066,1058.41781651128));
#429=CARTESIAN_POINT('',(-692.256747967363,-93.2646169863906,1057.20747400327));
#430=CARTESIAN_POINT('',(-691.165454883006,-101.034144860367,1054.63923814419));
#431=CARTESIAN_POINT('',(-690.591600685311,-104.882883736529,1053.28188684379));
#432=CARTESIAN_POINT('',(-689.389062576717,-112.516217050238,1050.41924011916));
#433=CARTESIAN_POINT('',(-688.760378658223,-116.300811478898,1048.91394467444));
#434=CARTESIAN_POINT('',(-687.451981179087,-123.800293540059,1045.75866286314));
#435=CARTESIAN_POINT('',(-686.772266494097,-127.515179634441,1044.10867330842));
#436=CARTESIAN_POINT('',(-685.365879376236,-134.869859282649,1040.66744688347));
#437=CARTESIAN_POINT('',(-684.639206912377,-138.509652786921,1038.87620992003));
#438=CARTESIAN_POINT('',(-683.143432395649,-145.707960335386,1035.15662002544));
#439=CARTESIAN_POINT('',(-682.374344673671,-149.266501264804,1033.22831334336));
#440=CARTESIAN_POINT('',(-680.797980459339,-156.298895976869,1029.23761281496));
#441=CARTESIAN_POINT('',(-679.990704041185,-159.772749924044,1027.17521922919));
#442=CARTESIAN_POINT('',(-678.342574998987,-166.631452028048,1022.9198886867));
#443=CARTESIAN_POINT('',(-677.501721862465,-170.016298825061,1020.72694973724));
#444=CARTESIAN_POINT('',(-675.791216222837,-176.692835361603,1016.21412085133));
#445=CARTESIAN_POINT('',(-674.921563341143,-179.984523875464,1013.89422924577));
#446=CARTESIAN_POINT('',(-673.113770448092,-186.634853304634,1009.01061067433));
#447=CARTESIAN_POINT('',(-672.174391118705,-189.988460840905,1006.44048562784));
#448=CARTESIAN_POINT('',(-670.275076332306,-196.584206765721,1001.16817670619));
#449=CARTESIAN_POINT('',(-669.315140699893,-199.826344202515,998.46599170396));
#450=CARTESIAN_POINT('',(-667.380677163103,-206.194948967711,992.933703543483));
#451=CARTESIAN_POINT('',(-666.406149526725,-209.321418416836,990.10360273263));
#452=CARTESIAN_POINT('',(-664.448456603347,-215.455013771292,984.31925224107));
#453=CARTESIAN_POINT('',(-663.465290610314,-218.462129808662,981.364992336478));
#454=CARTESIAN_POINT('',(-661.496045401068,-224.354376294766,975.33502794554));
#455=CARTESIAN_POINT('',(-660.50996494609,-227.239443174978,972.259261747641));
#456=CARTESIAN_POINT('',(-658.541645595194,-232.882115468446,965.991769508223));
#457=CARTESIAN_POINT('',(-657.559406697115,-235.639720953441,962.800043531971));
#458=CARTESIAN_POINT('',(-655.605082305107,-241.023708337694,956.304677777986));
#459=CARTESIAN_POINT('',(-654.632996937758,-243.650088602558,953.001036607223));
#460=CARTESIAN_POINT('',(-652.705343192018,-248.767888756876,946.285921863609));
#461=CARTESIAN_POINT('',(-651.749775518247,-251.259302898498,942.874443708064));
#462=CARTESIAN_POINT('',(-649.807324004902,-256.24255822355,935.74885727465));
#463=CARTESIAN_POINT('',(-648.821799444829,-258.726184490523,932.028627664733));
#464=CARTESIAN_POINT('',(-646.884185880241,-263.53332915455,924.478163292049));
#465=CARTESIAN_POINT('',(-645.932093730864,-265.856862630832,920.647938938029));
#466=CARTESIAN_POINT('',(-644.06875581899,-270.339750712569,912.882281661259));
#467=CARTESIAN_POINT('',(-643.157514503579,-272.49908746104,908.946837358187));
#468=CARTESIAN_POINT('',(-641.383543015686,-276.648680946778,900.977093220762));
#469=CARTESIAN_POINT('',(-640.520812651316,-278.638938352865,896.942793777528));
#470=CARTESIAN_POINT('',(-638.851643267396,-282.444940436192,888.783488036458));
#471=CARTESIAN_POINT('',(-638.045179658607,-284.260761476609,884.658522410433));
#472=CARTESIAN_POINT('',(-636.495319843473,-287.714338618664,876.323018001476));
#473=CARTESIAN_POINT('',(-635.751923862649,-289.35209408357,872.112478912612));
#474=CARTESIAN_POINT('',(-634.33513847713,-292.444996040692,863.613550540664));
#475=CARTESIAN_POINT('',(-633.661744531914,-293.900154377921,859.325166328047));
#476=CARTESIAN_POINT('',(-632.39139015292,-296.623731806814,850.678342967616));
#477=CARTESIAN_POINT('',(-631.794428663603,-297.892153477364,846.319904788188));
#478=CARTESIAN_POINT('',(-630.7119867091,-300.176869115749,837.771526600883));
#479=CARTESIAN_POINT('',(-630.222305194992,-301.202888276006,833.58471601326));
#480=CARTESIAN_POINT('',(-629.321423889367,-303.08064991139,825.163831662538));
#481=CARTESIAN_POINT('',(-628.910223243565,-303.932394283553,820.929758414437));
#482=CARTESIAN_POINT('',(-628.170206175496,-305.458936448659,812.422752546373));
#483=CARTESIAN_POINT('',(-627.841388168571,-306.133737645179,808.149820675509));
#484=CARTESIAN_POINT('',(-627.2693138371,-307.304218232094,799.573771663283));
#485=CARTESIAN_POINT('',(-627.026057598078,-307.799897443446,795.270654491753));
#486=CARTESIAN_POINT('',(-626.627622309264,-308.610234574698,786.645792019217));
#487=CARTESIAN_POINT('',(-626.472393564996,-308.9249946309,782.324058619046));
#488=CARTESIAN_POINT('',(-626.251351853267,-309.372844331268,773.668877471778));
#489=CARTESIAN_POINT('',(-626.18553925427,-309.505933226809,769.335429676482));
#490=CARTESIAN_POINT('',(-626.143993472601,-309.589973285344,760.666583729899));
#491=CARTESIAN_POINT('',(-626.168255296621,-309.540934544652,756.331185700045));
#492=CARTESIAN_POINT('',(-626.306605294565,-309.260910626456,747.667763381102));
#493=CARTESIAN_POINT('',(-626.420691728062,-309.029928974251,743.33973895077));
#494=CARTESIAN_POINT('',(-626.72342186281,-308.41547903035,735.085242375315));
#495=CARTESIAN_POINT('',(-626.904521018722,-308.047422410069,731.157334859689));
#496=CARTESIAN_POINT('',(-627.338795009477,-307.162057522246,723.322441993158));
#497=CARTESIAN_POINT('',(-627.591968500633,-306.644752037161,719.415456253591));
#498=CARTESIAN_POINT('',(-628.168315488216,-305.462353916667,711.629412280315));
#499=CARTESIAN_POINT('',(-628.491484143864,-304.797271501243,707.750352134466));
#500=CARTESIAN_POINT('',(-629.205253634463,-303.321068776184,700.026372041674));
#501=CARTESIAN_POINT('',(-629.595854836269,-302.509947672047,696.181452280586));
#502=CARTESIAN_POINT('',(-630.441503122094,-300.743611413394,688.531401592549));
#503=CARTESIAN_POINT('',(-630.896560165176,-299.78837399,684.726276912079));
#504=CARTESIAN_POINT('',(-631.867606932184,-297.736234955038,677.162319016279));
#505=CARTESIAN_POINT('',(-632.383596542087,-296.639333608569,673.403485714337));
#506=CARTESIAN_POINT('',(-633.472704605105,-294.306370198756,665.937529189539));
#507=CARTESIAN_POINT('',(-634.045824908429,-293.070303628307,662.23040764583));
#508=CARTESIAN_POINT('',(-635.245061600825,-290.461739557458,654.873192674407));
#509=CARTESIAN_POINT('',(-635.871178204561,-289.089241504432,651.223099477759));
#510=CARTESIAN_POINT('',(-637.186571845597,-286.178492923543,643.903994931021));
#511=CARTESIAN_POINT('',(-637.876946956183,-284.637225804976,640.236380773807));
#512=CARTESIAN_POINT('',(-639.303668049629,-281.418139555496,632.970698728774));
#513=CARTESIAN_POINT('',(-640.040014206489,-279.740319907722,629.372631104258));
#514=CARTESIAN_POINT('',(-641.553623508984,-276.251359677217,622.250758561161));
#515=CARTESIAN_POINT('',(-642.330884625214,-274.440225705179,618.726949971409));
#516=CARTESIAN_POINT('',(-643.92130334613,-270.687565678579,611.75736614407));
#517=CARTESIAN_POINT('',(-644.734463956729,-268.746028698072,608.311597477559));
#518=CARTESIAN_POINT('',(-646.391639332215,-264.735353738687,601.501546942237));
#519=CARTESIAN_POINT('',(-647.235661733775,-262.666184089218,598.137285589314));
#520=CARTESIAN_POINT('',(-648.949203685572,-258.403671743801,591.494697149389));
#521=CARTESIAN_POINT('',(-649.818725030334,-256.210320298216,588.216376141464));
#522=CARTESIAN_POINT('',(-651.577982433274,-251.702674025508,581.749507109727));
#523=CARTESIAN_POINT('',(-652.4677186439,-249.388378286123,578.560959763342));
#524=CARTESIAN_POINT('',(-654.262187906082,-244.641935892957,572.277125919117));
#525=CARTESIAN_POINT('',(-655.166921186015,-242.20978744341,569.181840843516));
#526=CARTESIAN_POINT('',(-657.074383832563,-236.989360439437,562.792537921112));
#527=CARTESIAN_POINT('',(-658.07811100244,-234.189414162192,559.508341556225));
#528=CARTESIAN_POINT('',(-660.090497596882,-228.455719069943,553.06092755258));
#529=CARTESIAN_POINT('',(-661.099156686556,-225.521979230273,549.897701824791));
#530=CARTESIAN_POINT('',(-663.114918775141,-219.524178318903,543.695881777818));
#531=CARTESIAN_POINT('',(-664.12202153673,-216.460099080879,540.657304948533));
#532=CARTESIAN_POINT('',(-666.127823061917,-210.20645801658,534.709866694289));
#533=CARTESIAN_POINT('',(-667.126522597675,-207.016907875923,531.800993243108));
#534=CARTESIAN_POINT('',(-669.109458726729,-200.515179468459,526.116006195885));
#535=CARTESIAN_POINT('',(-670.093690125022,-197.202958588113,523.339939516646));
#536=CARTESIAN_POINT('',(-672.040942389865,-190.461365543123,517.926037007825));
#537=CARTESIAN_POINT('',(-673.00396326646,-187.03199343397,515.288201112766));
#538=CARTESIAN_POINT('',(-674.902544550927,-180.060700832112,510.155162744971));
#539=CARTESIAN_POINT('',(-675.838104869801,-176.518779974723,507.659960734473));
#540=CARTESIAN_POINT('',(-677.675662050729,-169.32725911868,502.816638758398));
#541=CARTESIAN_POINT('',(-678.577658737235,-165.67765855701,500.468519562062));
#542=CARTESIAN_POINT('',(-680.36805932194,-158.167285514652,495.857116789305));
#543=CARTESIAN_POINT('',(-681.255286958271,-154.303459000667,493.598346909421));
#544=CARTESIAN_POINT('',(-682.981645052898,-146.473191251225,489.246248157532));
#545=CARTESIAN_POINT('',(-683.820775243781,-142.506749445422,487.152920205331));
#546=CARTESIAN_POINT('',(-685.444977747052,-134.477541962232,483.136444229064));
#547=CARTESIAN_POINT('',(-686.230047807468,-130.414772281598,481.213303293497));
#548=CARTESIAN_POINT('',(-687.740394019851,-122.200003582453,477.542023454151));
#549=CARTESIAN_POINT('',(-688.465670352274,-118.048004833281,475.793884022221));
#550=CARTESIAN_POINT('',(-689.850738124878,-109.664265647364,472.477979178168));
#551=CARTESIAN_POINT('',(-690.510561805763,-105.432565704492,470.910124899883));
#552=CARTESIAN_POINT('',(-691.760185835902,-96.8953370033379,467.958107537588));
#553=CARTESIAN_POINT('',(-692.34998588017,-92.5898079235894,466.57394525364));
#554=CARTESIAN_POINT('',(-693.45501921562,-83.9136987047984,463.993431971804));
#555=CARTESIAN_POINT('',(-693.970257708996,-79.5431231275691,462.797067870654));
#556=CARTESIAN_POINT('',(-694.922213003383,-70.7456149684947,460.5956887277));
#557=CARTESIAN_POINT('',(-695.358931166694,-66.3186833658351,459.590670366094));
#558=CARTESIAN_POINT('',(-696.12283822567,-57.7280100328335,457.838407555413));
#559=CARTESIAN_POINT('',(-696.45553844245,-53.5674212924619,457.078081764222));
#560=CARTESIAN_POINT('',(-697.047718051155,-45.2135188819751,455.727929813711));
#561=CARTESIAN_POINT('',(-697.307198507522,-41.0202056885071,455.138101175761));
#562=CARTESIAN_POINT('',(-697.75112282,-32.6091369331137,454.130668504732));
#563=CARTESIAN_POINT('',(-697.935569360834,-28.3913822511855,453.71305830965));
#564=CARTESIAN_POINT('',(-698.228143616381,-19.9396281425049,453.051266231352));
#565=CARTESIAN_POINT('',(-698.336271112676,-15.7056286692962,452.807084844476));
#566=CARTESIAN_POINT('',(-698.475421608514,-7.23113401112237,452.49293087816));
#567=CARTESIAN_POINT('',(-698.50646696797,-2.99064106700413,452.422907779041));
#568=CARTESIAN_POINT('',(-698.491298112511,5.48951284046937,452.457135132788));
#569=CARTESIAN_POINT('',(-698.445083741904,9.72917380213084,452.561385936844));
#570=CARTESIAN_POINT('',(-698.275725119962,18.1989856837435,452.943841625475));
#571=CARTESIAN_POINT('',(-698.152582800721,22.4291368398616,453.222042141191));
#572=CARTESIAN_POINT('',(-697.830238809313,30.871536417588,453.951561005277));
#573=CARTESIAN_POINT('',(-697.631037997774,35.0837850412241,454.402877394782));
#574=CARTESIAN_POINT('',(-697.171659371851,43.2392280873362,455.446220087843));
#575=CARTESIAN_POINT('',(-696.915673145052,47.1838971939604,456.028601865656));
#576=CARTESIAN_POINT('',(-696.339015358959,55.0431685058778,457.344349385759));
#577=CARTESIAN_POINT('',(-696.018344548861,58.9577710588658,458.07771337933));
#578=CARTESIAN_POINT('',(-695.314295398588,66.7501643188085,459.693550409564));
#579=CARTESIAN_POINT('',(-694.930920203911,70.6279568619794,460.576015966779));
#580=CARTESIAN_POINT('',(-694.103767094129,78.3406219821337,462.487940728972));
#581=CARTESIAN_POINT('',(-693.659988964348,82.1754944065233,463.517400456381));
#582=CARTESIAN_POINT('',(-692.714650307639,89.7964788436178,465.720961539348));
#583=CARTESIAN_POINT('',(-692.213086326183,93.5825879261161,466.895071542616));
#584=CARTESIAN_POINT('',(-691.155148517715,101.100043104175,469.385234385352));
#585=CARTESIAN_POINT('',(-690.59877479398,104.83138930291,470.701286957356));
#586=CARTESIAN_POINT('',(-689.434422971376,112.233976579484,473.472538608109));
#587=CARTESIAN_POINT('',(-688.826443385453,115.905215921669,474.927741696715));
#588=CARTESIAN_POINT('',(-687.562361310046,123.182337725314,477.974274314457));
#589=CARTESIAN_POINT('',(-686.906258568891,126.788219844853,479.565604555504));
#590=CARTESIAN_POINT('',(-685.528473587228,134.041070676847,482.932960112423));
#591=CARTESIAN_POINT('',(-684.805384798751,137.685817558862,484.713195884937));
#592=CARTESIAN_POINT('',(-683.316214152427,144.895658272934,488.411613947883));
#593=CARTESIAN_POINT('',(-682.550132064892,148.460751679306,490.329796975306));
#594=CARTESIAN_POINT('',(-680.979424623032,155.506595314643,494.300554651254));
#595=CARTESIAN_POINT('',(-680.174799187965,158.987345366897,496.353129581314));
#596=CARTESIAN_POINT('',(-678.531624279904,165.86008778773,500.589083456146));
#597=CARTESIAN_POINT('',(-677.693074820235,169.252080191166,502.772462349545));
#598=CARTESIAN_POINT('',(-675.986516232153,175.944334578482,507.267227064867));
#599=CARTESIAN_POINT('',(-675.118496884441,179.244564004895,509.57865747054));
#600=CARTESIAN_POINT('',(-673.358178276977,185.748116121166,514.325242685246));
#601=CARTESIAN_POINT('',(-672.465879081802,188.951439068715,516.76039716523));
#602=CARTESIAN_POINT('',(-670.662011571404,195.257448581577,521.750883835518));
#603=CARTESIAN_POINT('',(-669.750443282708,198.360135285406,524.306215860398));
#604=CARTESIAN_POINT('',(-667.913074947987,204.461552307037,529.533754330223));
#605=CARTESIAN_POINT('',(-666.987273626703,207.460273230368,532.205971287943));
#606=CARTESIAN_POINT('',(-665.052085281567,213.586289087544,537.882515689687));
#607=CARTESIAN_POINT('',(-664.041950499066,216.704602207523,540.896289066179));
#608=CARTESIAN_POINT('',(-662.017912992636,222.811311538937,547.051503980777));
#609=CARTESIAN_POINT('',(-661.004010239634,225.799706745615,550.192946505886));
#610=CARTESIAN_POINT('',(-658.97916181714,231.642557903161,556.599263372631));
#611=CARTESIAN_POINT('',(-657.968216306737,234.497006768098,559.86414422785));
#612=CARTESIAN_POINT('',(-655.9562075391,240.067644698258,566.512721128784));
#613=CARTESIAN_POINT('',(-654.955144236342,242.783834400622,569.896416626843));
#614=CARTESIAN_POINT('',(-652.96948002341,248.074777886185,576.779335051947));
#615=CARTESIAN_POINT('',(-651.984885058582,250.649481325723,580.278598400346));
#616=CARTESIAN_POINT('',(-650.039491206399,255.652329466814,587.38694913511));
#617=CARTESIAN_POINT('',(-649.078692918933,258.080470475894,590.996039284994));
#618=CARTESIAN_POINT('',(-647.187898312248,262.786042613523,598.319271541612));
#619=CARTESIAN_POINT('',(-646.257903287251,265.063467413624,602.033418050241));
#620=CARTESIAN_POINT('',(-644.435859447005,269.46306217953,609.561148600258));
#621=CARTESIAN_POINT('',(-643.543806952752,271.585247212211,613.374722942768));
#622=CARTESIAN_POINT('',(-641.784309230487,275.717809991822,621.185923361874));
#623=CARTESIAN_POINT('',(-640.917916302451,277.72444750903,625.185766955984));
#624=CARTESIAN_POINT('',(-639.239372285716,281.566457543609,633.278078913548));
#625=CARTESIAN_POINT('',(-638.427221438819,283.401829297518,637.370547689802));
#626=CARTESIAN_POINT('',(-636.864271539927,286.896871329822,645.641573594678));
#627=CARTESIAN_POINT('',(-636.113474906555,288.556534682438,649.82013410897));
#628=CARTESIAN_POINT('',(-634.680126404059,291.695671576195,658.255937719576));
#629=CARTESIAN_POINT('',(-633.99757431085,293.175145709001,662.513180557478));
#630=CARTESIAN_POINT('',(-632.707694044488,295.948579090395,671.095111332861));
#631=CARTESIAN_POINT('',(-632.100306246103,297.242685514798,675.419742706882));
#632=CARTESIAN_POINT('',(-630.966068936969,299.642841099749,684.13137847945));
#633=CARTESIAN_POINT('',(-630.439219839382,300.748889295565,688.518383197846));
#634=CARTESIAN_POINT('',(-629.47144085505,302.769235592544,697.345312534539));
#635=CARTESIAN_POINT('',(-629.030503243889,303.68355093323,701.785232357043));
#636=CARTESIAN_POINT('',(-628.239090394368,305.317408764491,710.708728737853));
#637=CARTESIAN_POINT('',(-627.888613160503,306.03695555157,715.192304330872));
#638=CARTESIAN_POINT('',(-627.307479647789,307.226260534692,723.812751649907));
#639=CARTESIAN_POINT('',(-627.069202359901,307.711985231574,727.946915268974));
#640=CARTESIAN_POINT('',(-626.673755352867,308.516540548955,736.235281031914));
#641=CARTESIAN_POINT('',(-626.516584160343,308.835374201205,740.389482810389));
#642=CARTESIAN_POINT('',(-626.284803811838,309.30512948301,748.709466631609));
#643=CARTESIAN_POINT('',(-626.210190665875,309.456059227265,752.875248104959));
#644=CARTESIAN_POINT('',(-626.144205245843,309.589550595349,761.210187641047));
#645=CARTESIAN_POINT('',(-626.152833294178,309.572111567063,765.379345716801));
#646=CARTESIAN_POINT('',(-626.253241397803,309.368938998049,773.711762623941));
#647=CARTESIAN_POINT('',(-626.345005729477,309.183237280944,777.875022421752));
#648=CARTESIAN_POINT('',(-626.610812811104,308.644179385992,786.188038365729));
#649=CARTESIAN_POINT('',(-626.784855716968,308.290822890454,790.337794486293));
#650=CARTESIAN_POINT('',(-627.21361348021,307.417581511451,798.615468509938));
#651=CARTESIAN_POINT('',(-627.468326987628,306.89769941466,802.743386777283));
#652=CARTESIAN_POINT('',(-628.056114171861,305.693010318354,810.969421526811));
#653=CARTESIAN_POINT('',(-628.389187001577,305.008205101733,815.067538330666));
#654=CARTESIAN_POINT('',(-629.108598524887,303.521434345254,822.982909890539));
#655=CARTESIAN_POINT('',(-629.490575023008,302.728893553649,826.802336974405));
#656=CARTESIAN_POINT('',(-630.318237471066,301.001804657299,834.401925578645));
#657=CARTESIAN_POINT('',(-630.763922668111,300.067258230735,838.182087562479));
#658=CARTESIAN_POINT('',(-631.71562620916,298.05847158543,845.697169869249));
#659=CARTESIAN_POINT('',(-632.221641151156,296.984239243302,849.432092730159));
#660=CARTESIAN_POINT('',(-633.290324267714,294.698501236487,856.851478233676));
#661=CARTESIAN_POINT('',(-633.852992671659,293.486995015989,860.535940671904));
#662=CARTESIAN_POINT('',(-635.031101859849,290.929085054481,867.849995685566));
#663=CARTESIAN_POINT('',(-635.646553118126,289.582654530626,871.479577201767));
#664=CARTESIAN_POINT('',(-636.925891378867,286.757846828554,878.678314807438));
#665=CARTESIAN_POINT('',(-637.589778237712,285.279470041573,882.24747107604));
#666=CARTESIAN_POINT('',(-638.961566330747,282.193581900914,889.320905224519));
#667=CARTESIAN_POINT('',(-639.669467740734,280.586070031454,892.825182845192));
#668=CARTESIAN_POINT('',(-641.124775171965,277.244645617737,899.764947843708));
#669=CARTESIAN_POINT('',(-641.872184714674,275.510721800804,903.200429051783));
#670=CARTESIAN_POINT('',(-643.450610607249,271.804842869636,910.215359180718));
#671=CARTESIAN_POINT('',(-644.283918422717,269.824758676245,913.790000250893));
#672=CARTESIAN_POINT('',(-645.984260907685,265.728250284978,920.852463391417));
#673=CARTESIAN_POINT('',(-646.851298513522,263.611814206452,924.340277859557));
#674=CARTESIAN_POINT('',(-648.613269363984,259.246248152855,931.224515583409));
#675=CARTESIAN_POINT('',(-649.508202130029,256.997120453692,934.62094040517));
#676=CARTESIAN_POINT('',(-651.320210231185,252.369585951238,941.318435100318));
#677=CARTESIAN_POINT('',(-652.237285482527,249.991179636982,944.619505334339));
#678=CARTESIAN_POINT('',(-654.088184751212,245.10756386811,951.123685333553));
#679=CARTESIAN_POINT('',(-655.022014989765,242.602306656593,954.326757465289));
#680=CARTESIAN_POINT('',(-656.900297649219,237.469402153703,960.629659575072));
#681=CARTESIAN_POINT('',(-657.844749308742,234.841763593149,963.729496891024));
#682=CARTESIAN_POINT('',(-659.738778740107,229.467020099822,969.822842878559));
#683=CARTESIAN_POINT('',(-660.688357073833,226.7199018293,972.816339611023));
#684=CARTESIAN_POINT('',(-662.586853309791,221.110107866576,978.692780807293));
#685=CARTESIAN_POINT('',(-663.535771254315,218.247440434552,981.575733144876));
#686=CARTESIAN_POINT('',(-665.509740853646,212.155972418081,987.47346922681));
#687=CARTESIAN_POINT('',(-666.534238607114,208.916978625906,990.477921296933));
#688=CARTESIAN_POINT('',(-668.569012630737,202.310827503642,996.347593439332));
#689=CARTESIAN_POINT('',(-669.579288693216,198.943668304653,999.212811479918));
#690=CARTESIAN_POINT('',(-671.578814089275,192.085669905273,1004.79950324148));
#691=CARTESIAN_POINT('',(-672.568061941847,188.594822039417,1007.52096685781));
#692=CARTESIAN_POINT('',(-674.518727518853,181.494601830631,1012.81519338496));
#693=CARTESIAN_POINT('',(-675.480145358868,177.885229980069,1015.3879569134));
#694=CARTESIAN_POINT('',(-677.369101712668,170.551155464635,1020.38137679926));
#695=CARTESIAN_POINT('',(-678.296621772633,166.826391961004,1022.80195080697));
#696=CARTESIAN_POINT('',(-680.11085561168,159.268878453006,1027.48470135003));
#697=CARTESIAN_POINT('',(-680.997569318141,155.436128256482,1029.74687760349));
#698=CARTESIAN_POINT('',(-682.723961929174,147.668779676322,1034.10789954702));
#699=CARTESIAN_POINT('',(-683.563643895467,143.73418794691,1036.20675587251));
#700=CARTESIAN_POINT('',(-685.190111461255,135.769223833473,1040.23655201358));
#701=CARTESIAN_POINT('',(-685.976897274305,131.738851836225,1042.16749250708));
#702=CARTESIAN_POINT('',(-687.483180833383,123.636198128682,1045.83547925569));
#703=CARTESIAN_POINT('',(-688.203351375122,119.564939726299,1047.57450915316));
#704=CARTESIAN_POINT('',(-689.581389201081,111.342419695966,1050.87962912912));
#705=CARTESIAN_POINT('',(-690.239256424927,107.191157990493,1052.44571904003));
#706=CARTESIAN_POINT('',(-691.488034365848,98.8153804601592,1055.40106885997));
#707=CARTESIAN_POINT('',(-692.078933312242,94.5908519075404,1056.79029768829));
#708=CARTESIAN_POINT('',(-693.189282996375,86.0772661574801,1059.3877133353));
#709=CARTESIAN_POINT('',(-693.70873465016,81.7882097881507,1060.59590247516));
#710=CARTESIAN_POINT('',(-694.67098825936,73.1658000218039,1062.82466825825));
#711=CARTESIAN_POINT('',(-695.113996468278,68.8326003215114,1063.84575021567));
#712=CARTESIAN_POINT('',(-695.921767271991,60.1189564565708,1065.7013260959));
#713=CARTESIAN_POINT('',(-696.286526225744,55.7385101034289,1066.53581133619));
#714=CARTESIAN_POINT('',(-696.934773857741,46.9425933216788,1068.01505192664));
#715=CARTESIAN_POINT('',(-697.218313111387,42.5271464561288,1068.65992535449));
#716=CARTESIAN_POINT('',(-697.702190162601,33.668585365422,1069.75847938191));
#717=CARTESIAN_POINT('',(-697.90254294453,29.2254762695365,1070.21219441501));
#718=CARTESIAN_POINT('',(-698.133633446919,22.7140856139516,1070.73497064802));
#719=CARTESIAN_POINT('',(-698.197660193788,20.6527609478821,1070.87971141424));
#720=CARTESIAN_POINT('',(-698.307487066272,16.5275251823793,1071.12788720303));
#721=CARTESIAN_POINT('',(-698.353290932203,14.4636147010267,1071.23133070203));
#722=CARTESIAN_POINT('',(-698.42660909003,10.3337822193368,1071.39687325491));
#723=CARTESIAN_POINT('',(-698.454123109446,8.26786018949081,1071.45897169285));
#724=CARTESIAN_POINT('',(-698.49082131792,4.13464920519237,1071.54179033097));
#725=CARTESIAN_POINT('',(-698.500001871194,2.06736006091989,1071.56250232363));
#726=CARTESIAN_POINT('',(-698.5,0.,1071.5625));
#727=B_SPLINE_CURVE_WITH_KNOTS('',3,(#413,#414,#415,#416,#417,#418,#419,#420,#421,#422,#423,
#424,#425,#426,#427,#428,#429,#430,#431,#432,#433,#434,#435,#436,#437,#438,#439,#440,#441,#442,
#443,#444,#445,#446,#447,#448,#449,#450,#451,#452,#453,#454,#455,#456,#457,#458,#459,#460,#461,
#462,#463,#464,#465,#466,#467,#468,#469,#470,#471,#472,#473,#474,#475,#476,#477,#478,#479,#480,
#481,#482,#483,#484,#485,#486,#487,#488,#489,#490,#491,#492,#493,#494,#495,#496,#497,#498,#499,
#500,#501,#502,#503,#504,#505,#506,#507,#508,#509,#510,#511,#512,#513,#514,#515,#516,#517,#518,
#519,#520,#521,#522,#523,#524,#525,#526,#527,#528,#529,#530,#531,#532,#533,#534,#535,#536,#537,
#538,#539,#540,#541,#542,#543,#544,#545,#546,#547,#548,#549,#550,#551,#552,#553,#554,#555,#556,
#557,#558,#559,#560,#561,#562,#563,#564,#565,#566,#567,#568,#569,#570,#571,#572,#573,#574,#575,
#576,#577,#578,#579,#580,#581,#582,#583,#584,#585,#586,#587,#588,#589,#590,#591,#592,#593,#594,
#595,#596,#597,#598,#599,#600,#601,#602,#603,#604,#605,#606,#607,#608,#609,#610,#611,#612,#613,
#614,#615,#616,#617,#618,#619,#620,#621,#622,#623,#624,#625,#626,#627,#628,#629,#630,#631,#632,
#633,#634,#635,#636,#637,#638,#639,#640,#641,#642,#643,#644,#645,#646,#647,#648,#649,#650,#651,
#652,#653,#654,#655,#656,#657,#658,#659,#660,#661,#662,#663,#664,#665,#666,#667,#668,#669,#670,
#671,#672,#673,#674,#675,#676,#677,#678,#679,#680,#681,#682,#683,#684,#685,#686,#687,#688,#689,
#690,#691,#692,#693,#694,#695,#696,#697,#698,#699,#700,#701,#702,#703,#704,#705,#706,#707,#708,
#709,#710,#711,#712,#713,#714,#715,#716,#717,#718,#719,#720,#721,#722,#723,#724,#725,#726),
.UNSPECIFIED.,.T.,.F.,(4,2,2,2,2,2,2,2,2,2,2,2,2,2,2,2,2,2,2,2,2,2,2,2,2,2,2,2,2,2,2,2,2,2,2,2,
2,2,2,2,2,2,2,2,2,2,2,2,2,2,2,2,2,2,2,2,2,2,2,2,2,2,2,2,2,2,2,2,2,2,2,2,2,2,2,2,2,2,2,2,2,2,2,2,
2,2,2,2,2,2,2,2,2,2,2,2,2,2,2,2,2,2,2,2,2,2,2,2,2,2,2,2,2,2,2,2,2,2,2,2,2,2,2,2,2,2,2,2,2,2,2,2,
2,2,2,2,2,2,2,2,2,2,2,2,2,2,2,2,2,2,2,2,2,2,2,2,4),(0.,12.3715617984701,24.744979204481,
37.1247834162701,49.5041029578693,61.910257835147,74.3165513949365,86.7209887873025,
99.1253858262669,111.485509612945,123.845635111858,136.206033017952,148.566439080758,
160.922694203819,173.278925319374,185.635345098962,197.99192737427,210.973439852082,
223.955063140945,236.936448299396,249.918904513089,262.908041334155,275.897170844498,
288.88646209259,301.876306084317,315.61316750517,329.348733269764,343.085790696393,
356.822793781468,370.553755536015,384.284766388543,398.014886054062,411.744816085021,
424.755702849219,437.766447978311,450.776942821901,463.787450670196,476.79060631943,
489.793815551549,502.796303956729,515.798540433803,527.642855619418,539.486950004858,
551.330225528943,563.173565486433,575.018737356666,586.863887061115,598.709420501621,
610.555001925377,622.665061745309,634.775167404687,646.884672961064,658.995194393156,
671.108733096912,683.223126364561,695.337611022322,707.452280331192,720.741319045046,
734.029467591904,747.319474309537,760.608246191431,773.901678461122,787.195104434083,
800.488573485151,813.78211205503,827.465878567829,841.149721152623,854.834133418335,
868.518504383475,882.196100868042,895.873756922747,909.55045822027,923.226922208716,
935.950488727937,948.673870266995,961.396796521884,974.119759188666,986.839030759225,
999.558327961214,1012.27730572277,1024.99613956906,1036.97957973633,1048.96288111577,
1060.94558154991,1072.92832457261,1084.91178431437,1096.89522147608,1108.87900406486,
1120.8628493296,1133.22017472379,1145.57756614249,1157.93498344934,1170.29239590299,
1182.65413821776,1195.01584765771,1207.37754008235,1219.74034662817,1233.0948451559,
1246.44944694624,1259.80475441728,1273.16000033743,1286.51996795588,1299.88027202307,
1313.2411367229,1326.60070295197,1340.27046874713,1353.94029547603,1367.61066081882,
1381.2809812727,1394.94038705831,1408.59986291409,1422.25811006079,1435.91605588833,
1448.42021330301,1460.92414355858,1473.42746947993,1485.93084382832,1498.43185389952,
1510.93288765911,1523.43371223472,1535.9344016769,1547.68945553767,1559.44437049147,
1571.19862289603,1582.95292289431,1594.70956079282,1606.46616383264,1618.22281383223,
1629.98051350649,1642.48871655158,1654.99801094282,1667.50709083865,1680.01612341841,
1692.52990093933,1705.04278707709,1717.55707365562,1730.07046721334,1743.67184694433,
1757.27342508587,1770.87595802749,1784.47843446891,1798.08820896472,1811.69800768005,
1825.30691937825,1838.91577613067,1852.36729047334,1865.81881785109,1879.27270588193,
1892.72642140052,1906.14324946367,1919.56070169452,1932.96978064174,1946.37644316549,
1952.57822667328,1958.7787365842,1964.97933886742,1971.18117069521),.UNSPECIFIED.);
#728=CARTESIAN_POINT('',(-698.5,0.,1071.5625));
#729=VERTEX_POINT('',#728);
#730=EDGE_CURVE('E37',#729,#729,#727,.T.);
#731=ORIENTED_EDGE('',*,*,#730,.F.);
#732=EDGE_LOOP('',(#731));
#733=FACE_BOUND('',#732,.T.);
#734=ORIENTED_EDGE('',*,*,#42,.T.);
#735=EDGE_LOOP('',(#734));
#736=FACE_BOUND('',#735,.T.);
#737=ORIENTED_EDGE('',*,*,#70,.F.);
#738=EDGE_LOOP('',(#737));
#739=FACE_BOUND('',#738,.T.);
#740=ADVANCED_FACE('F66',(#733,#736,#739),#412,.F.);
#741=CARTESIAN_POINT('',(-1018.286,0.,762.));
#742=DIRECTION('',(1.,0.,0.));
#743=DIRECTION('',(0.,0.,-1.));
#744=AXIS2_PLACEMENT_3D('',#741,#742,#743);
#745=CYLINDRICAL_SURFACE('',#744,309.5625);
#746=ORIENTED_EDGE('',*,*,#730,.T.);
#747=EDGE_LOOP('',(#746));
#748=FACE_BOUND('',#747,.T.);
#749=ORIENTED_EDGE('',*,*,#397,.F.);
#750=EDGE_LOOP('',(#749));
#751=FACE_BOUND('',#750,.T.);
#752=ADVANCED_FACE('F63',(#748,#751),#745,.F.);
#753=CLOSED_SHELL('',(#46,#74,#407,#740,#752));
#754=MANIFOLD_SOLID_BREP('B2',#753);
#755=ADVANCED_BREP_SHAPE_REPRESENTATION('',(#18,#754),#14);
#756=SHAPE_DEFINITION_REPRESENTATION(#9,#755);
ENDSEC;
END-ISO-10303-21;
